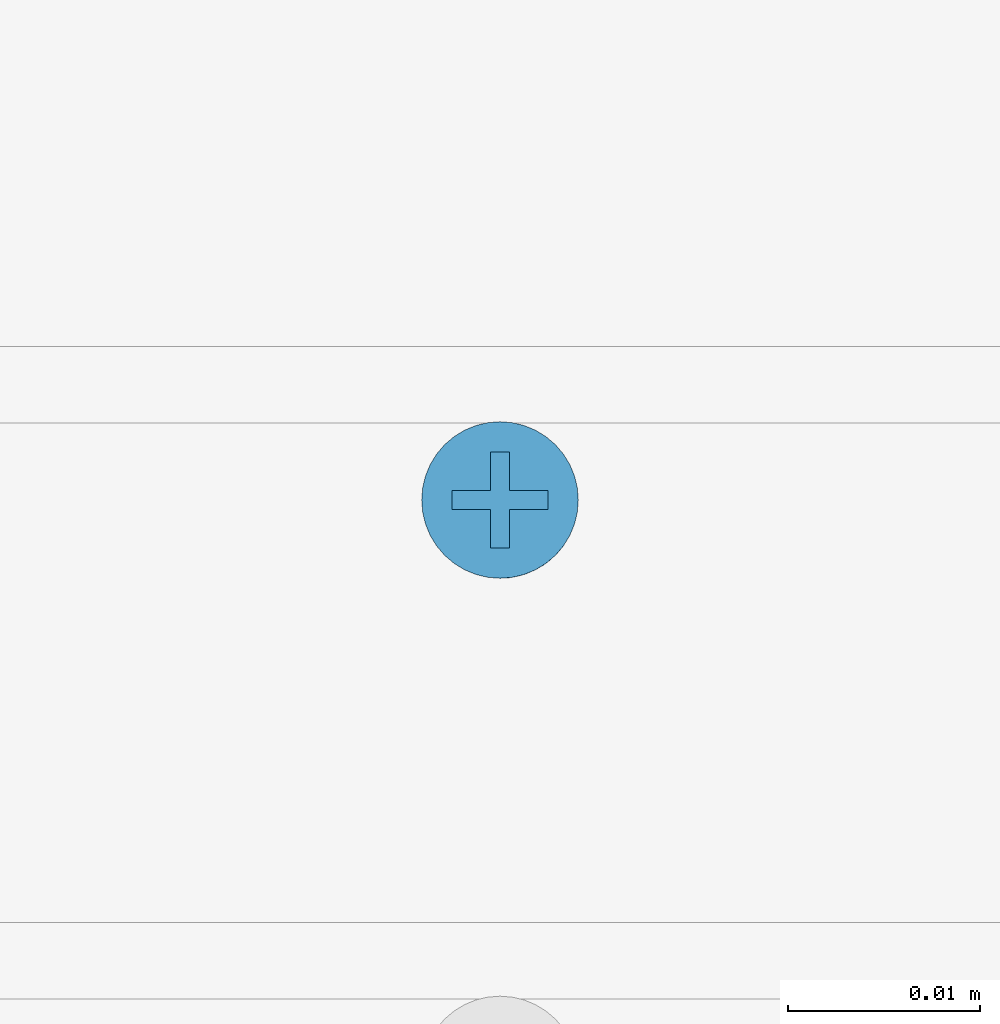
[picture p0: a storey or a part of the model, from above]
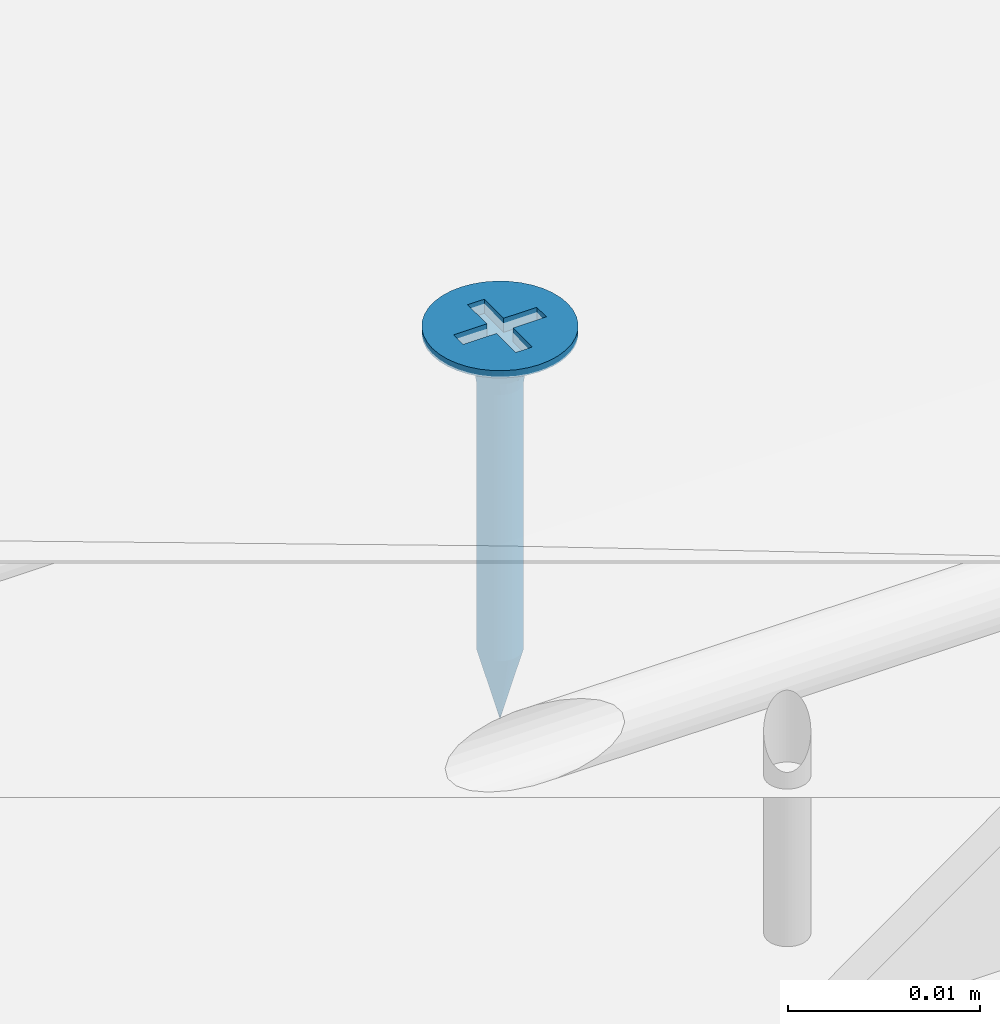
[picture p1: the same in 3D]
Properties of the parts of a building model (IFC2X3)

# File
Description: ViewDefinition [CoordinationView]
Time: 2022-01-05T16:21:10
Made in: SketchUp Pro 2015

# IfcProject, Default Project
Description: Description of Default Project

# IfcSite, Default Site
Description: Description of Default Site; RefLatitude: 24, 28, 0; RefLongitude: 54, 25, 0; RefElevation: 10 mm

# IfcBuilding, Default Building
Description: Description of Default Building

# IfcBuildingStorey, Default Building Storey
In: Default Building
Description: Description of Default Building Storey; Elevation: 0 mm

# IfcSlab (24)
In: Default Building Storey
Description: Description of Object
PredefinedType - IfcSlabTypeEnum: floor
Name
Dylatacja Isover Twist
Wełna ISOVER
4 x Klej RIGIPS Rigidur
2 x Dedykowana masa szpachlowa Rigips - konstrukcyjna
12 x Wkręt RIGIPS Rigidur 3,9x19 mm
STROP
3 x RIGIPS Rigidur E20

# IfcWall (43)
In: Default Building Storey
Description: Description of Object
Name
ŚCIANA
3 x Dedykowana masa szpachlowa Rigips - konstrukcyjna
4 x Płyta gipsowo-kartonowa RIGIPS PRO (4PRO™)
Taśma spoinowa RIGIPS
Dedykowana masa szpachlowa Rigips - wykończeniowa
11 x Wkręt RIGIPS TN 35
8 x Wkręt RIGIPS TN 25
3 x Wełna mineralna szklana lub skalna ISOVER
3 x Profil RIGIPS CW50 ULTRASTIL®
6 x Kołek rozporowy min. fi 6
Taśma uszczelniająca piankowa RIGIPS
Profil RIGIPS UW50 ULTRASTIL®
